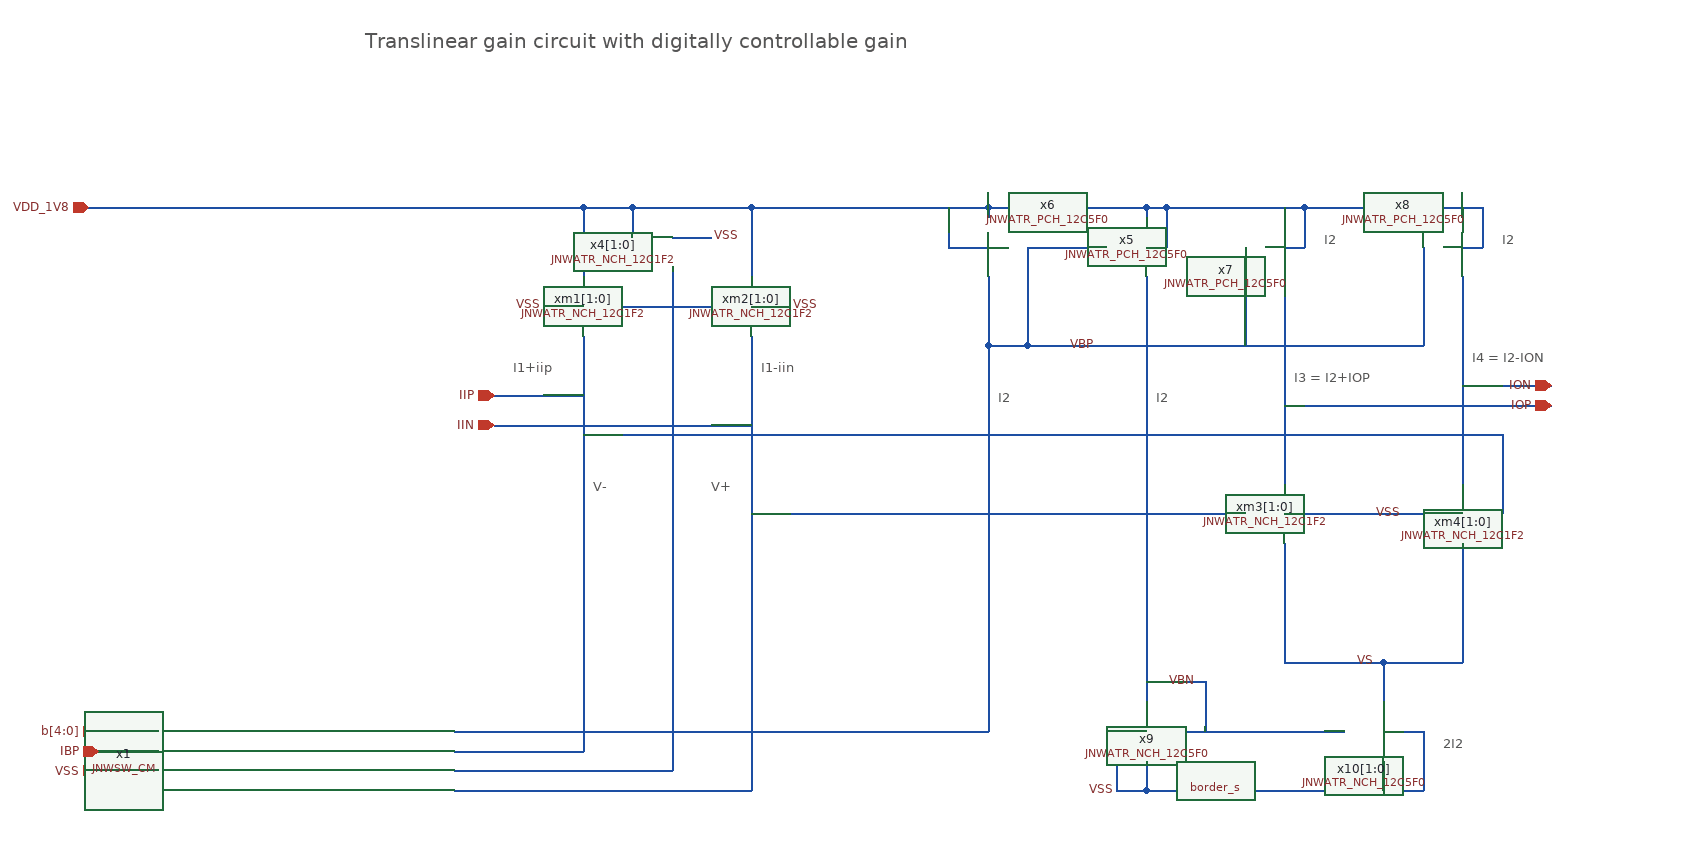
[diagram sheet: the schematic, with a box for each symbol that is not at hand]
v {xschem version=3.4.5 file_version=1.2
}
G {}
K {}
V {}
S {}
E {}
T {Translinear gain circuit with digitally controllable gain} 390 -930 0 0 0.6 0.6 {}
T {I1+iip} 540 -600 0 0 0.4 0.4 {}
T {I1-iin} 790 -600 0 0 0.4 0.4 {}
T {2I2} 1480 -220 0 0 0.4 0.4 {}
T {V+} 740 -480 0 0 0.4 0.4 {}
T {V-} 620 -480 0 0 0.4 0.4 {}
T {I3 = I2+IOP} 1330 -590 0 0 0.4 0.4 {}
T {I4 = I2-ION} 1510 -610 0 0 0.4 0.4 {}
T {I2} 1540 -730 0 0 0.4 0.4 {}
T {I2} 1360 -730 0 0 0.4 0.4 {}
T {I2} 1030 -570 0 0 0.4 0.4 {}
T {I2} 1190 -570 0 0 0.4 0.4 {}
N 650 -650 740 -650 {
lab=#net1}
N 660 -750 660 -720 {
lab=VDD_1V8}
N 660 -750 700 -750 {
lab=VDD_1V8}
N 610 -750 610 -680 {
lab=VDD_1V8}
N 610 -750 660 -750 {
lab=VDD_1V8}
N 700 -750 780 -750 {
lab=VDD_1V8}
N 780 -750 780 -680 {
lab=VDD_1V8}
N 700 -720 740 -720 {
lab=VSS}
N 780 -650 820 -650 {
lab=VSS}
N 570 -650 610 -650 {
lab=VSS}
N 610 -620 610 -480 {
lab=IIP}
N 780 -620 780 -480 {
lab=IIN}
N 610 -480 610 -200 {
lab=IIP}
N 480 -200 610 -200 {
lab=IIP}
N 780 -480 780 -180 {
lab=IIN}
N 780 -180 780 -160 {
lab=IIN}
N 480 -160 780 -160 {
lab=IIN}
N 700 -190 700 -180 {
lab=#net1}
N 480 -180 700 -180 {
lab=#net1}
N 1020 -750 1020 -740 {
lab=VDD_1V8}
N 780 -750 1020 -750 {
lab=VDD_1V8}
N 1020 -680 1020 -610 {
lab=VBP}
N 1020 -610 1060 -610 {
lab=VBP}
N 1060 -710 1060 -610 {
lab=VBP}
N 980 -710 1020 -710 {
lab=VDD_1V8}
N 980 -750 980 -710 {
lab=VDD_1V8}
N 1060 -710 1140 -710 {
lab=VBP}
N 1020 -750 1180 -750 {
lab=VDD_1V8}
N 1180 -750 1180 -740 {
lab=VDD_1V8}
N 1180 -710 1200 -710 {
lab=VDD_1V8}
N 1200 -750 1200 -710 {
lab=VDD_1V8}
N 1180 -750 1200 -750 {
lab=VDD_1V8}
N 1320 -710 1340 -710 {
lab=VDD_1V8}
N 1340 -750 1340 -710 {
lab=VDD_1V8}
N 1500 -710 1520 -710 {
lab=VDD_1V8}
N 1520 -750 1520 -710 {
lab=VDD_1V8}
N 1220 -220 1380 -220 {
lab=VBN}
N 1150 -220 1180 -220 {
lab=VSS}
N 1150 -220 1150 -160 {
lab=VSS}
N 1150 -160 1180 -160 {
lab=VSS}
N 1180 -190 1180 -160 {
lab=VSS}
N 1180 -680 1180 -250 {
lab=VBN}
N 1320 -440 1500 -440 {
lab=VSS}
N 1320 -410 1320 -290 {
lab=VS}
N 1320 -290 1420 -290 {
lab=VS}
N 1420 -290 1420 -250 {
lab=VS}
N 1500 -410 1500 -290 {
lab=VS}
N 1420 -290 1500 -290 {
lab=VS}
N 1420 -220 1460 -220 {
lab=VSS}
N 1460 -220 1460 -160 {
lab=VSS}
N 1180 -160 1460 -160 {
lab=VSS}
N 1420 -190 1420 -160 {
lab=VSS}
N 1060 -610 1290 -610 {
lab=VBP}
N 1290 -610 1300 -610 {
lab=VBP}
N 1280 -710 1280 -610 {
lab=VBP}
N 1310 -610 1460 -610 {
lab=VBP}
N 1460 -710 1460 -610 {
lab=VBP}
N 1320 -680 1320 -470 {
lab=IOP}
N 1300 -610 1310 -610 {
lab=VBP}
N 1200 -750 1340 -750 {
lab=VDD_1V8}
N 1320 -750 1320 -740 {
lab=VDD_1V8}
N 1340 -750 1520 -750 {
lab=VDD_1V8}
N 1500 -750 1500 -740 {
lab=VDD_1V8}
N 1500 -680 1500 -470 {
lab=ION}
N 780 -440 1280 -440 {
lab=IIN}
N 1540 -520 1540 -440 {
lab=IIP}
N 610 -520 1540 -520 {
lab=IIP}
N 1240 -270 1240 -220 {
lab=VBN}
N 1180 -270 1240 -270 {
lab=VBN}
N 1500 -570 1590 -570 {
lab=ION}
N 1320 -550 1590 -550 {
lab=IOP}
N 520 -530 780 -530 {
lab=IIN}
N 520 -560 610 -560 {
lab=IIP}
N 480 -220 1020 -220 {
lab=VBP}
N 1020 -610 1020 -220 {
lab=VBP}
N 120 -220 180 -220 {
lab=b[4:0]}
N 110 -200 180 -200 {
lab=IBP}
N 120 -180 180 -180 {
lab=VSS}
N 110 -750 610 -750 {
lab=VDD_1V8}
N 700 -690 700 -650 {
lab=#net1}
N 700 -650 700 -190 {
lab=#net1}
C {devices/ipin.sym} 110 -750 0 0 {name=p1 lab=VDD_1V8}
C {devices/ipin.sym} 120 -180 0 0 {name=p2 lab=VSS}
C {devices/ipin.sym} 120 -220 0 0 {name=p3 lab=b[4:0]

}
C {JNW_SV_SKY130A/JNWSW_CM.sym} 330 -190 0 0 {name=x1}
C {JNW_ATR_SKY130A/JNWATR_NCH_12C1F2.sym} 740 -650 0 0 {name=xm2[1:0]}
C {JNW_ATR_SKY130A/JNWATR_NCH_12C1F2.sym} 650 -650 0 1 {name=xm1[1:0]}
C {JNW_ATR_SKY130A/JNWATR_NCH_12C1F2.sym} 660 -720 0 0 {name=x4[1:0]}
C {devices/lab_wire.sym} 740 -720 0 1 {name=p6 sig_type=std_logic lab=VSS}
C {devices/lab_wire.sym} 820 -650 0 1 {name=p7 sig_type=std_logic lab=VSS}
C {devices/lab_wire.sym} 570 -650 0 0 {name=p8 sig_type=std_logic lab=VSS}
C {JNW_ATR_SKY130A/JNWATR_PCH_12C5F0.sym} 1060 -710 0 1 {name=x6 }
C {JNW_ATR_SKY130A/JNWATR_PCH_12C5F0.sym} 1140 -710 0 0 {name=x5 }
C {JNW_ATR_SKY130A/JNWATR_PCH_12C5F0.sym} 1280 -710 0 0 {name=x7 }
C {JNW_ATR_SKY130A/JNWATR_PCH_12C5F0.sym} 1460 -710 0 0 {name=x8 }
C {JNW_ATR_SKY130A/JNWATR_NCH_12C5F0.sym} 1380 -220 0 0 {name=x10[1:0]}
C {JNW_ATR_SKY130A/JNWATR_NCH_12C1F2.sym} 1280 -440 0 0 {name=xm3[1:0]}
C {JNW_ATR_SKY130A/JNWATR_NCH_12C5F0.sym} 1220 -220 0 1 {name=x9 }
C {JNW_ATR_SKY130A/JNWATR_NCH_12C1F2.sym} 1540 -440 0 1 {name=xm4[1:0]}
C {devices/opin.sym} 1590 -570 2 1 {name=p9 lab=ION

}
C {devices/opin.sym} 1590 -550 2 1 {name=p10 lab=IOP

}
C {devices/ipin.sym} 520 -560 0 0 {name=p11 lab=IIP

}
C {devices/ipin.sym} 520 -530 0 0 {name=p12 lab=IIN

}
C {devices/ipin.sym} 120 -200 0 0 {name=p13 lab=IBP

}
C {devices/lab_wire.sym} 1150 -160 0 0 {name=p14 sig_type=std_logic lab=VSS}
C {devices/lab_wire.sym} 1410 -440 0 1 {name=p4 sig_type=std_logic lab=VSS}
C {devices/lab_wire.sym} 1390 -290 0 1 {name=p5 sig_type=std_logic lab=VS}
C {devices/lab_wire.sym} 1100 -610 0 1 {name=p15 sig_type=std_logic lab=VBP}
C {devices/lab_wire.sym} 1200 -270 0 1 {name=p16 sig_type=std_logic lab=VBN}
C {cborder/border_s.sym} 1250 -170 0 0 {}
